One B-rep face of a CAD part: STEP entity #216319.
In plain terms, the planar face has unit normal (0, -1, 0).
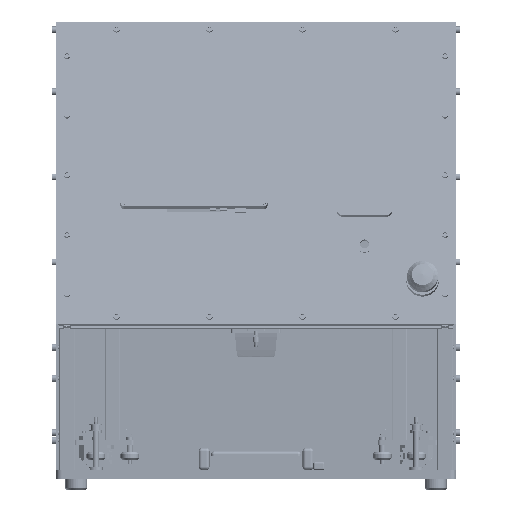
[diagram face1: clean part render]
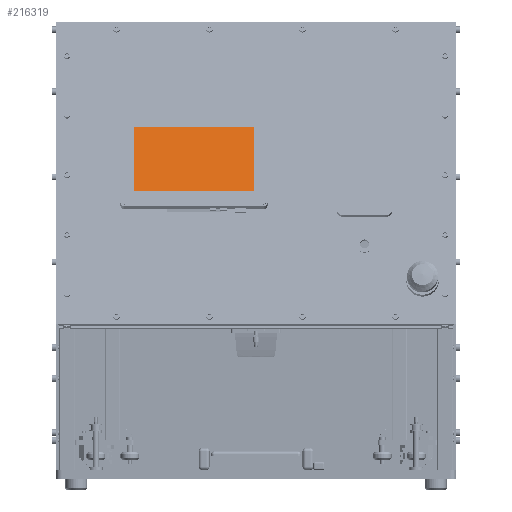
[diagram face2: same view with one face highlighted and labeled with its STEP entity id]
Its self-contained STEP definition (entity closure, numbers rounded to 3 decimals):
#216103 = EDGE_CURVE('',#216104,#216106,#216108,.T.);
#216104 = VERTEX_POINT('',#216105);
#216105 = CARTESIAN_POINT('',(-77.1,-1.45,-40.95));
#216106 = VERTEX_POINT('',#216107);
#216107 = CARTESIAN_POINT('',(-77.1,-1.45,44.95));
#216108 = SURFACE_CURVE('',#216109,(#216113,#216125),.PCURVE_S1.);
#216109 = LINE('',#216110,#216111);
#216110 = CARTESIAN_POINT('',(-77.1,-1.45,-40.95));
#216111 = VECTOR('',#216112,1.);
#216112 = DIRECTION('',(0.,0.,1.));
#216113 = PCURVE('',#216114,#216119);
#216114 = PLANE('',#216115);
#216115 = AXIS2_PLACEMENT_3D('',#216116,#216117,#216118);
#216116 = CARTESIAN_POINT('',(-77.1,-1.45,-40.95));
#216117 = DIRECTION('',(1.,0.,0.));
#216118 = DIRECTION('',(0.,0.,1.));
#216119 = DEFINITIONAL_REPRESENTATION('',(#216120),#216124);
#216120 = LINE('',#216121,#216122);
#216121 = CARTESIAN_POINT('',(0.,0.));
#216122 = VECTOR('',#216123,1.);
#216123 = DIRECTION('',(1.,0.));
#216124 = ( GEOMETRIC_REPRESENTATION_CONTEXT(2) 
PARAMETRIC_REPRESENTATION_CONTEXT() REPRESENTATION_CONTEXT('2D SPACE',''
  ) );
#216125 = PCURVE('',#216126,#216131);
#216126 = PLANE('',#216127);
#216127 = AXIS2_PLACEMENT_3D('',#216128,#216129,#216130);
#216128 = CARTESIAN_POINT('',(-77.1,-1.45,-40.95));
#216129 = DIRECTION('',(0.,1.,0.));
#216130 = DIRECTION('',(0.,0.,1.));
#216131 = DEFINITIONAL_REPRESENTATION('',(#216132),#216136);
#216132 = LINE('',#216133,#216134);
#216133 = CARTESIAN_POINT('',(0.,0.));
#216134 = VECTOR('',#216135,1.);
#216135 = DIRECTION('',(1.,0.));
#216136 = ( GEOMETRIC_REPRESENTATION_CONTEXT(2) 
PARAMETRIC_REPRESENTATION_CONTEXT() REPRESENTATION_CONTEXT('2D SPACE',''
  ) );
#216154 = PLANE('',#216155);
#216155 = AXIS2_PLACEMENT_3D('',#216156,#216157,#216158);
#216156 = CARTESIAN_POINT('',(-77.1,-1.45,-40.95));
#216157 = DIRECTION('',(0.,0.,1.));
#216158 = DIRECTION('',(1.,0.,0.));
#216208 = PLANE('',#216209);
#216209 = AXIS2_PLACEMENT_3D('',#216210,#216211,#216212);
#216210 = CARTESIAN_POINT('',(-77.1,-1.45,44.95));
#216211 = DIRECTION('',(0.,0.,1.));
#216212 = DIRECTION('',(1.,0.,0.));
#216223 = EDGE_CURVE('',#216224,#216226,#216228,.T.);
#216224 = VERTEX_POINT('',#216225);
#216225 = CARTESIAN_POINT('',(77.1,-1.45,-40.95));
#216226 = VERTEX_POINT('',#216227);
#216227 = CARTESIAN_POINT('',(77.1,-1.45,44.95));
#216228 = SURFACE_CURVE('',#216229,(#216233,#216245),.PCURVE_S1.);
#216229 = LINE('',#216230,#216231);
#216230 = CARTESIAN_POINT('',(77.1,-1.45,-40.95));
#216231 = VECTOR('',#216232,1.);
#216232 = DIRECTION('',(0.,0.,1.));
#216233 = PCURVE('',#216234,#216239);
#216234 = PLANE('',#216235);
#216235 = AXIS2_PLACEMENT_3D('',#216236,#216237,#216238);
#216236 = CARTESIAN_POINT('',(77.1,-1.45,-40.95));
#216237 = DIRECTION('',(1.,0.,0.));
#216238 = DIRECTION('',(0.,0.,1.));
#216239 = DEFINITIONAL_REPRESENTATION('',(#216240),#216244);
#216240 = LINE('',#216241,#216242);
#216241 = CARTESIAN_POINT('',(0.,0.));
#216242 = VECTOR('',#216243,1.);
#216243 = DIRECTION('',(1.,0.));
#216244 = ( GEOMETRIC_REPRESENTATION_CONTEXT(2) 
PARAMETRIC_REPRESENTATION_CONTEXT() REPRESENTATION_CONTEXT('2D SPACE',''
  ) );
#216245 = PCURVE('',#216126,#216246);
#216246 = DEFINITIONAL_REPRESENTATION('',(#216247),#216251);
#216247 = LINE('',#216248,#216249);
#216248 = CARTESIAN_POINT('',(0.,154.2));
#216249 = VECTOR('',#216250,1.);
#216250 = DIRECTION('',(1.,0.));
#216251 = ( GEOMETRIC_REPRESENTATION_CONTEXT(2) 
PARAMETRIC_REPRESENTATION_CONTEXT() REPRESENTATION_CONTEXT('2D SPACE',''
  ) );
#216319 = ADVANCED_FACE('',(#216320),#216126,.F.);
#216320 = FACE_BOUND('',#216321,.F.);
#216321 = EDGE_LOOP('',(#216322,#216343,#216344,#216365));
#216322 = ORIENTED_EDGE('',*,*,#216323,.F.);
#216323 = EDGE_CURVE('',#216104,#216224,#216324,.T.);
#216324 = SURFACE_CURVE('',#216325,(#216329,#216336),.PCURVE_S1.);
#216325 = LINE('',#216326,#216327);
#216326 = CARTESIAN_POINT('',(-77.1,-1.45,-40.95));
#216327 = VECTOR('',#216328,1.);
#216328 = DIRECTION('',(1.,0.,0.));
#216329 = PCURVE('',#216126,#216330);
#216330 = DEFINITIONAL_REPRESENTATION('',(#216331),#216335);
#216331 = LINE('',#216332,#216333);
#216332 = CARTESIAN_POINT('',(0.,0.));
#216333 = VECTOR('',#216334,1.);
#216334 = DIRECTION('',(0.,1.));
#216335 = ( GEOMETRIC_REPRESENTATION_CONTEXT(2) 
PARAMETRIC_REPRESENTATION_CONTEXT() REPRESENTATION_CONTEXT('2D SPACE',''
  ) );
#216336 = PCURVE('',#216154,#216337);
#216337 = DEFINITIONAL_REPRESENTATION('',(#216338),#216342);
#216338 = LINE('',#216339,#216340);
#216339 = CARTESIAN_POINT('',(0.,0.));
#216340 = VECTOR('',#216341,1.);
#216341 = DIRECTION('',(1.,0.));
#216342 = ( GEOMETRIC_REPRESENTATION_CONTEXT(2) 
PARAMETRIC_REPRESENTATION_CONTEXT() REPRESENTATION_CONTEXT('2D SPACE',''
  ) );
#216343 = ORIENTED_EDGE('',*,*,#216103,.T.);
#216344 = ORIENTED_EDGE('',*,*,#216345,.T.);
#216345 = EDGE_CURVE('',#216106,#216226,#216346,.T.);
#216346 = SURFACE_CURVE('',#216347,(#216351,#216358),.PCURVE_S1.);
#216347 = LINE('',#216348,#216349);
#216348 = CARTESIAN_POINT('',(-77.1,-1.45,44.95));
#216349 = VECTOR('',#216350,1.);
#216350 = DIRECTION('',(1.,0.,0.));
#216351 = PCURVE('',#216126,#216352);
#216352 = DEFINITIONAL_REPRESENTATION('',(#216353),#216357);
#216353 = LINE('',#216354,#216355);
#216354 = CARTESIAN_POINT('',(85.9,0.));
#216355 = VECTOR('',#216356,1.);
#216356 = DIRECTION('',(0.,1.));
#216357 = ( GEOMETRIC_REPRESENTATION_CONTEXT(2) 
PARAMETRIC_REPRESENTATION_CONTEXT() REPRESENTATION_CONTEXT('2D SPACE',''
  ) );
#216358 = PCURVE('',#216208,#216359);
#216359 = DEFINITIONAL_REPRESENTATION('',(#216360),#216364);
#216360 = LINE('',#216361,#216362);
#216361 = CARTESIAN_POINT('',(0.,0.));
#216362 = VECTOR('',#216363,1.);
#216363 = DIRECTION('',(1.,0.));
#216364 = ( GEOMETRIC_REPRESENTATION_CONTEXT(2) 
PARAMETRIC_REPRESENTATION_CONTEXT() REPRESENTATION_CONTEXT('2D SPACE',''
  ) );
#216365 = ORIENTED_EDGE('',*,*,#216223,.F.);
